VERSION 5.8 ;
BUSBITCHARS "[]" ;
DIVIDERCHAR "/" ;
UNITS
    DATABASE MICRONS 1000 ;
END UNITS

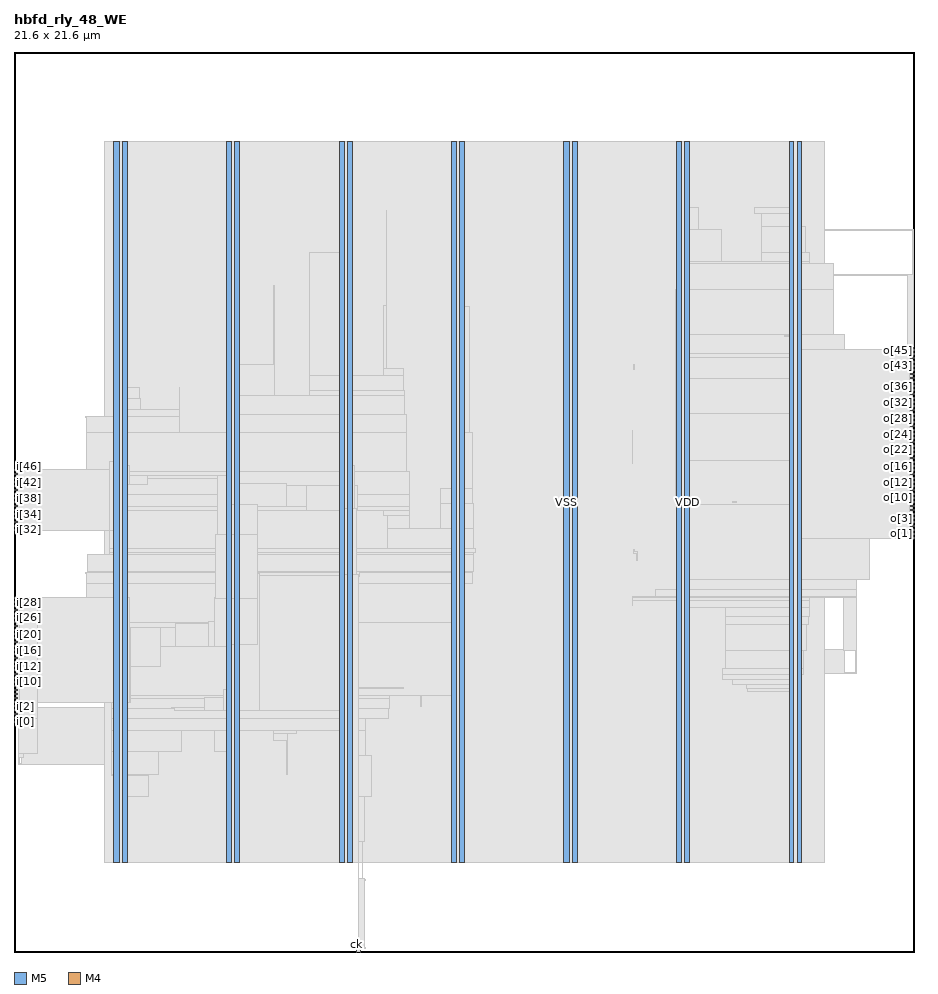
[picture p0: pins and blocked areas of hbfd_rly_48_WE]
MACRO hbfd_rly_48_WE
  FOREIGN hbfd_rly_48_WE 0 0 ;
  CLASS BLOCK ;
  SIZE 21.6 BY 21.6 ;
  PIN ck
    DIRECTION INPUT ;
    USE SIGNAL ;
    PORT
      LAYER M5 ;
        RECT  8.208 0 8.232 0.084 ;
    END
  END ck
  PIN i[0]
    DIRECTION INPUT ;
    USE SIGNAL ;
    PORT
      LAYER M4 ;
        RECT  0 5.52 0.084 5.544 ;
    END
  END i[0]
  PIN i[10]
    DIRECTION INPUT ;
    USE SIGNAL ;
    PORT
      LAYER M4 ;
        RECT  0 6.48 0.084 6.504 ;
    END
  END i[10]
  PIN i[11]
    DIRECTION INPUT ;
    USE SIGNAL ;
    PORT
      LAYER M4 ;
        RECT  0 6.576 0.084 6.6 ;
    END
  END i[11]
  PIN i[12]
    DIRECTION INPUT ;
    USE SIGNAL ;
    PORT
      LAYER M4 ;
        RECT  0 6.672 0.084 6.696 ;
    END
  END i[12]
  PIN i[13]
    DIRECTION INPUT ;
    USE SIGNAL ;
    PORT
      LAYER M4 ;
        RECT  0 6.768 0.084 6.792 ;
    END
  END i[13]
  PIN i[14]
    DIRECTION INPUT ;
    USE SIGNAL ;
    PORT
      LAYER M4 ;
        RECT  0 6.864 0.084 6.888 ;
    END
  END i[14]
  PIN i[15]
    DIRECTION INPUT ;
    USE SIGNAL ;
    PORT
      LAYER M4 ;
        RECT  0 6.96 0.084 6.984 ;
    END
  END i[15]
  PIN i[16]
    DIRECTION INPUT ;
    USE SIGNAL ;
    PORT
      LAYER M4 ;
        RECT  0 7.056 0.084 7.08 ;
    END
  END i[16]
  PIN i[17]
    DIRECTION INPUT ;
    USE SIGNAL ;
    PORT
      LAYER M4 ;
        RECT  0 7.152 0.084 7.176 ;
    END
  END i[17]
  PIN i[18]
    DIRECTION INPUT ;
    USE SIGNAL ;
    PORT
      LAYER M4 ;
        RECT  0 7.248 0.084 7.272 ;
    END
  END i[18]
  PIN i[19]
    DIRECTION INPUT ;
    USE SIGNAL ;
    PORT
      LAYER M4 ;
        RECT  0 7.344 0.084 7.368 ;
    END
  END i[19]
  PIN i[1]
    DIRECTION INPUT ;
    USE SIGNAL ;
    PORT
      LAYER M4 ;
        RECT  0 5.616 0.084 5.64 ;
    END
  END i[1]
  PIN i[20]
    DIRECTION INPUT ;
    USE SIGNAL ;
    PORT
      LAYER M4 ;
        RECT  0 7.44 0.084 7.464 ;
    END
  END i[20]
  PIN i[21]
    DIRECTION INPUT ;
    USE SIGNAL ;
    PORT
      LAYER M4 ;
        RECT  0 7.536 0.084 7.56 ;
    END
  END i[21]
  PIN i[22]
    DIRECTION INPUT ;
    USE SIGNAL ;
    PORT
      LAYER M4 ;
        RECT  0 7.632 0.084 7.656 ;
    END
  END i[22]
  PIN i[23]
    DIRECTION INPUT ;
    USE SIGNAL ;
    PORT
      LAYER M4 ;
        RECT  0 7.728 0.084 7.752 ;
    END
  END i[23]
  PIN i[24]
    DIRECTION INPUT ;
    USE SIGNAL ;
    PORT
      LAYER M4 ;
        RECT  0 7.824 0.084 7.848 ;
    END
  END i[24]
  PIN i[25]
    DIRECTION INPUT ;
    USE SIGNAL ;
    PORT
      LAYER M4 ;
        RECT  0 7.92 0.084 7.944 ;
    END
  END i[25]
  PIN i[26]
    DIRECTION INPUT ;
    USE SIGNAL ;
    PORT
      LAYER M4 ;
        RECT  0 8.016 0.084 8.04 ;
    END
  END i[26]
  PIN i[27]
    DIRECTION INPUT ;
    USE SIGNAL ;
    PORT
      LAYER M4 ;
        RECT  0 8.112 0.084 8.136 ;
    END
  END i[27]
  PIN i[28]
    DIRECTION INPUT ;
    USE SIGNAL ;
    PORT
      LAYER M4 ;
        RECT  0 8.208 0.084 8.232 ;
    END
  END i[28]
  PIN i[29]
    DIRECTION INPUT ;
    USE SIGNAL ;
    PORT
      LAYER M4 ;
        RECT  0 8.304 0.084 8.328 ;
    END
  END i[29]
  PIN i[2]
    DIRECTION INPUT ;
    USE SIGNAL ;
    PORT
      LAYER M4 ;
        RECT  0 5.712 0.084 5.736 ;
    END
  END i[2]
  PIN i[30]
    DIRECTION INPUT ;
    USE SIGNAL ;
    PORT
      LAYER M4 ;
        RECT  0 8.4 0.084 8.424 ;
    END
  END i[30]
  PIN i[31]
    DIRECTION INPUT ;
    USE SIGNAL ;
    PORT
      LAYER M4 ;
        RECT  0 8.496 0.084 8.52 ;
    END
  END i[31]
  PIN i[32]
    DIRECTION INPUT ;
    USE SIGNAL ;
    PORT
      LAYER M4 ;
        RECT  0 10.128 0.084 10.152 ;
    END
  END i[32]
  PIN i[33]
    DIRECTION INPUT ;
    USE SIGNAL ;
    PORT
      LAYER M4 ;
        RECT  0 10.224 0.084 10.248 ;
    END
  END i[33]
  PIN i[34]
    DIRECTION INPUT ;
    USE SIGNAL ;
    PORT
      LAYER M4 ;
        RECT  0 10.32 0.084 10.344 ;
    END
  END i[34]
  PIN i[35]
    DIRECTION INPUT ;
    USE SIGNAL ;
    PORT
      LAYER M4 ;
        RECT  0 10.416 0.084 10.44 ;
    END
  END i[35]
  PIN i[36]
    DIRECTION INPUT ;
    USE SIGNAL ;
    PORT
      LAYER M4 ;
        RECT  0 10.512 0.084 10.536 ;
    END
  END i[36]
  PIN i[37]
    DIRECTION INPUT ;
    USE SIGNAL ;
    PORT
      LAYER M4 ;
        RECT  0 10.608 0.084 10.632 ;
    END
  END i[37]
  PIN i[38]
    DIRECTION INPUT ;
    USE SIGNAL ;
    PORT
      LAYER M4 ;
        RECT  0 10.704 0.084 10.728 ;
    END
  END i[38]
  PIN i[39]
    DIRECTION INPUT ;
    USE SIGNAL ;
    PORT
      LAYER M4 ;
        RECT  0 10.8 0.084 10.824 ;
    END
  END i[39]
  PIN i[3]
    DIRECTION INPUT ;
    USE SIGNAL ;
    PORT
      LAYER M4 ;
        RECT  0 5.808 0.084 5.832 ;
    END
  END i[3]
  PIN i[40]
    DIRECTION INPUT ;
    USE SIGNAL ;
    PORT
      LAYER M4 ;
        RECT  0 10.896 0.084 10.92 ;
    END
  END i[40]
  PIN i[41]
    DIRECTION INPUT ;
    USE SIGNAL ;
    PORT
      LAYER M4 ;
        RECT  0 10.992 0.084 11.016 ;
    END
  END i[41]
  PIN i[42]
    DIRECTION INPUT ;
    USE SIGNAL ;
    PORT
      LAYER M4 ;
        RECT  0 11.088 0.084 11.112 ;
    END
  END i[42]
  PIN i[43]
    DIRECTION INPUT ;
    USE SIGNAL ;
    PORT
      LAYER M4 ;
        RECT  0 11.184 0.084 11.208 ;
    END
  END i[43]
  PIN i[44]
    DIRECTION INPUT ;
    USE SIGNAL ;
    PORT
      LAYER M4 ;
        RECT  0 11.28 0.084 11.304 ;
    END
  END i[44]
  PIN i[45]
    DIRECTION INPUT ;
    USE SIGNAL ;
    PORT
      LAYER M4 ;
        RECT  0 11.376 0.084 11.4 ;
    END
  END i[45]
  PIN i[46]
    DIRECTION INPUT ;
    USE SIGNAL ;
    PORT
      LAYER M4 ;
        RECT  0 11.472 0.084 11.496 ;
    END
  END i[46]
  PIN i[47]
    DIRECTION INPUT ;
    USE SIGNAL ;
    PORT
      LAYER M4 ;
        RECT  0 11.568 0.084 11.592 ;
    END
  END i[47]
  PIN i[4]
    DIRECTION INPUT ;
    USE SIGNAL ;
    PORT
      LAYER M4 ;
        RECT  0 5.904 0.084 5.928 ;
    END
  END i[4]
  PIN i[5]
    DIRECTION INPUT ;
    USE SIGNAL ;
    PORT
      LAYER M4 ;
        RECT  0 6 0.084 6.024 ;
    END
  END i[5]
  PIN i[6]
    DIRECTION INPUT ;
    USE SIGNAL ;
    PORT
      LAYER M4 ;
        RECT  0 6.096 0.084 6.12 ;
    END
  END i[6]
  PIN i[7]
    DIRECTION INPUT ;
    USE SIGNAL ;
    PORT
      LAYER M4 ;
        RECT  0 6.192 0.084 6.216 ;
    END
  END i[7]
  PIN i[8]
    DIRECTION INPUT ;
    USE SIGNAL ;
    PORT
      LAYER M4 ;
        RECT  0 6.288 0.084 6.312 ;
    END
  END i[8]
  PIN i[9]
    DIRECTION INPUT ;
    USE SIGNAL ;
    PORT
      LAYER M4 ;
        RECT  0 6.384 0.084 6.408 ;
    END
  END i[9]
  PIN o[0]
    DIRECTION OUTPUT ;
    USE SIGNAL ;
    PORT
      LAYER M4 ;
        RECT  21.516 9.936 21.6 9.96 ;
    END
  END o[0]
  PIN o[10]
    DIRECTION OUTPUT ;
    USE SIGNAL ;
    PORT
      LAYER M4 ;
        RECT  21.516 10.896 21.6 10.92 ;
    END
  END o[10]
  PIN o[11]
    DIRECTION OUTPUT ;
    USE SIGNAL ;
    PORT
      LAYER M4 ;
        RECT  21.516 10.992 21.6 11.016 ;
    END
  END o[11]
  PIN o[12]
    DIRECTION OUTPUT ;
    USE SIGNAL ;
    PORT
      LAYER M4 ;
        RECT  21.516 11.088 21.6 11.112 ;
    END
  END o[12]
  PIN o[13]
    DIRECTION OUTPUT ;
    USE SIGNAL ;
    PORT
      LAYER M4 ;
        RECT  21.516 11.184 21.6 11.208 ;
    END
  END o[13]
  PIN o[14]
    DIRECTION OUTPUT ;
    USE SIGNAL ;
    PORT
      LAYER M4 ;
        RECT  21.516 11.28 21.6 11.304 ;
    END
  END o[14]
  PIN o[15]
    DIRECTION OUTPUT ;
    USE SIGNAL ;
    PORT
      LAYER M4 ;
        RECT  21.516 11.376 21.6 11.4 ;
    END
  END o[15]
  PIN o[16]
    DIRECTION OUTPUT ;
    USE SIGNAL ;
    PORT
      LAYER M4 ;
        RECT  21.516 11.472 21.6 11.496 ;
    END
  END o[16]
  PIN o[17]
    DIRECTION OUTPUT ;
    USE SIGNAL ;
    PORT
      LAYER M4 ;
        RECT  21.516 11.568 21.6 11.592 ;
    END
  END o[17]
  PIN o[18]
    DIRECTION OUTPUT ;
    USE SIGNAL ;
    PORT
      LAYER M4 ;
        RECT  21.516 11.664 21.6 11.688 ;
    END
  END o[18]
  PIN o[19]
    DIRECTION OUTPUT ;
    USE SIGNAL ;
    PORT
      LAYER M4 ;
        RECT  21.516 11.76 21.6 11.784 ;
    END
  END o[19]
  PIN o[1]
    DIRECTION OUTPUT ;
    USE SIGNAL ;
    PORT
      LAYER M4 ;
        RECT  21.516 10.032 21.6 10.056 ;
    END
  END o[1]
  PIN o[20]
    DIRECTION OUTPUT ;
    USE SIGNAL ;
    PORT
      LAYER M4 ;
        RECT  21.516 11.856 21.6 11.88 ;
    END
  END o[20]
  PIN o[21]
    DIRECTION OUTPUT ;
    USE SIGNAL ;
    PORT
      LAYER M4 ;
        RECT  21.516 11.952 21.6 11.976 ;
    END
  END o[21]
  PIN o[22]
    DIRECTION OUTPUT ;
    USE SIGNAL ;
    PORT
      LAYER M4 ;
        RECT  21.516 12.048 21.6 12.072 ;
    END
  END o[22]
  PIN o[23]
    DIRECTION OUTPUT ;
    USE SIGNAL ;
    PORT
      LAYER M4 ;
        RECT  21.516 12.144 21.6 12.168 ;
    END
  END o[23]
  PIN o[24]
    DIRECTION OUTPUT ;
    USE SIGNAL ;
    PORT
      LAYER M4 ;
        RECT  21.516 12.24 21.6 12.264 ;
    END
  END o[24]
  PIN o[25]
    DIRECTION OUTPUT ;
    USE SIGNAL ;
    PORT
      LAYER M4 ;
        RECT  21.516 12.336 21.6 12.36 ;
    END
  END o[25]
  PIN o[26]
    DIRECTION OUTPUT ;
    USE SIGNAL ;
    PORT
      LAYER M4 ;
        RECT  21.516 12.432 21.6 12.456 ;
    END
  END o[26]
  PIN o[27]
    DIRECTION OUTPUT ;
    USE SIGNAL ;
    PORT
      LAYER M4 ;
        RECT  21.516 12.528 21.6 12.552 ;
    END
  END o[27]
  PIN o[28]
    DIRECTION OUTPUT ;
    USE SIGNAL ;
    PORT
      LAYER M4 ;
        RECT  21.516 12.624 21.6 12.648 ;
    END
  END o[28]
  PIN o[29]
    DIRECTION OUTPUT ;
    USE SIGNAL ;
    PORT
      LAYER M4 ;
        RECT  21.516 12.72 21.6 12.744 ;
    END
  END o[29]
  PIN o[2]
    DIRECTION OUTPUT ;
    USE SIGNAL ;
    PORT
      LAYER M4 ;
        RECT  21.516 10.128 21.6 10.152 ;
    END
  END o[2]
  PIN o[30]
    DIRECTION OUTPUT ;
    USE SIGNAL ;
    PORT
      LAYER M4 ;
        RECT  21.516 12.816 21.6 12.84 ;
    END
  END o[30]
  PIN o[31]
    DIRECTION OUTPUT ;
    USE SIGNAL ;
    PORT
      LAYER M4 ;
        RECT  21.516 12.912 21.6 12.936 ;
    END
  END o[31]
  PIN o[32]
    DIRECTION OUTPUT ;
    USE SIGNAL ;
    PORT
      LAYER M4 ;
        RECT  21.516 13.008 21.6 13.032 ;
    END
  END o[32]
  PIN o[33]
    DIRECTION OUTPUT ;
    USE SIGNAL ;
    PORT
      LAYER M4 ;
        RECT  21.516 13.104 21.6 13.128 ;
    END
  END o[33]
  PIN o[34]
    DIRECTION OUTPUT ;
    USE SIGNAL ;
    PORT
      LAYER M4 ;
        RECT  21.516 13.2 21.6 13.224 ;
    END
  END o[34]
  PIN o[35]
    DIRECTION OUTPUT ;
    USE SIGNAL ;
    PORT
      LAYER M4 ;
        RECT  21.516 13.296 21.6 13.32 ;
    END
  END o[35]
  PIN o[36]
    DIRECTION OUTPUT ;
    USE SIGNAL ;
    PORT
      LAYER M4 ;
        RECT  21.516 13.392 21.6 13.416 ;
    END
  END o[36]
  PIN o[37]
    DIRECTION OUTPUT ;
    USE SIGNAL ;
    PORT
      LAYER M4 ;
        RECT  21.516 13.488 21.6 13.512 ;
    END
  END o[37]
  PIN o[38]
    DIRECTION OUTPUT ;
    USE SIGNAL ;
    PORT
      LAYER M4 ;
        RECT  21.516 13.584 21.6 13.608 ;
    END
  END o[38]
  PIN o[39]
    DIRECTION OUTPUT ;
    USE SIGNAL ;
    PORT
      LAYER M4 ;
        RECT  21.516 13.68 21.6 13.704 ;
    END
  END o[39]
  PIN o[3]
    DIRECTION OUTPUT ;
    USE SIGNAL ;
    PORT
      LAYER M4 ;
        RECT  21.516 10.224 21.6 10.248 ;
    END
  END o[3]
  PIN o[40]
    DIRECTION OUTPUT ;
    USE SIGNAL ;
    PORT
      LAYER M4 ;
        RECT  21.516 13.776 21.6 13.8 ;
    END
  END o[40]
  PIN o[41]
    DIRECTION OUTPUT ;
    USE SIGNAL ;
    PORT
      LAYER M4 ;
        RECT  21.516 13.872 21.6 13.896 ;
    END
  END o[41]
  PIN o[42]
    DIRECTION OUTPUT ;
    USE SIGNAL ;
    PORT
      LAYER M4 ;
        RECT  21.516 13.968 21.6 13.992 ;
    END
  END o[42]
  PIN o[43]
    DIRECTION OUTPUT ;
    USE SIGNAL ;
    PORT
      LAYER M4 ;
        RECT  21.516 14.064 21.6 14.088 ;
    END
  END o[43]
  PIN o[44]
    DIRECTION OUTPUT ;
    USE SIGNAL ;
    PORT
      LAYER M4 ;
        RECT  21.516 14.16 21.6 14.184 ;
    END
  END o[44]
  PIN o[45]
    DIRECTION OUTPUT ;
    USE SIGNAL ;
    PORT
      LAYER M4 ;
        RECT  21.516 14.256 21.6 14.28 ;
    END
  END o[45]
  PIN o[46]
    DIRECTION OUTPUT ;
    USE SIGNAL ;
    PORT
      LAYER M4 ;
        RECT  21.516 14.352 21.6 14.376 ;
    END
  END o[46]
  PIN o[47]
    DIRECTION OUTPUT ;
    USE SIGNAL ;
    PORT
      LAYER M4 ;
        RECT  21.516 14.448 21.6 14.472 ;
    END
  END o[47]
  PIN o[4]
    DIRECTION OUTPUT ;
    USE SIGNAL ;
    PORT
      LAYER M4 ;
        RECT  21.516 10.32 21.6 10.344 ;
    END
  END o[4]
  PIN o[5]
    DIRECTION OUTPUT ;
    USE SIGNAL ;
    PORT
      LAYER M4 ;
        RECT  21.516 10.416 21.6 10.44 ;
    END
  END o[5]
  PIN o[6]
    DIRECTION OUTPUT ;
    USE SIGNAL ;
    PORT
      LAYER M4 ;
        RECT  21.516 10.512 21.6 10.536 ;
    END
  END o[6]
  PIN o[7]
    DIRECTION OUTPUT ;
    USE SIGNAL ;
    PORT
      LAYER M4 ;
        RECT  21.516 10.608 21.6 10.632 ;
    END
  END o[7]
  PIN o[8]
    DIRECTION OUTPUT ;
    USE SIGNAL ;
    PORT
      LAYER M4 ;
        RECT  21.516 10.704 21.6 10.728 ;
    END
  END o[8]
  PIN o[9]
    DIRECTION OUTPUT ;
    USE SIGNAL ;
    PORT
      LAYER M4 ;
        RECT  21.516 10.8 21.6 10.824 ;
    END
  END o[9]
  PIN rs
    DIRECTION INPUT ;
    USE SIGNAL ;
    PORT
      LAYER M5 ;
        RECT  8.304 0 8.328 0.084 ;
    END
  END rs
  PIN VDD
    DIRECTION INOUT ;
    USE POWER ;
    PORT
      LAYER M5 ;
        RECT  18.792 2.151 18.912 19.449 ;
        RECT  16.092 2.151 16.212 19.449 ;
        RECT  13.392 2.151 13.512 19.449 ;
        RECT  10.692 2.151 10.812 19.449 ;
        RECT  7.992 2.151 8.112 19.449 ;
        RECT  5.292 2.151 5.412 19.449 ;
        RECT  2.592 2.151 2.712 19.449 ;
    END
  END VDD
  PIN VSS
    DIRECTION INOUT ;
    USE GROUND ;
    PORT
      LAYER M5 ;
        RECT  18.6 2.137 18.72 19.463 ;
        RECT  15.9 2.137 16.02 19.463 ;
        RECT  13.2 2.137 13.32 19.463 ;
        RECT  10.5 2.137 10.62 19.463 ;
        RECT  7.8 2.137 7.92 19.463 ;
        RECT  5.1 2.137 5.22 19.463 ;
        RECT  2.4 2.137 2.52 19.463 ;
    END
  END VSS
  # OT_OBS_CLOSED layer=M5 d_um=1.536 added=0
  OBS
    LAYER RVTN ;
     RECT  2.16 2.16 19.44 2.295 ;
     RECT  2.16 2.565 19.44 2.835 ;
     RECT  2.16 3.105 19.44 3.375 ;
     RECT  2.16 3.645 19.44 3.915 ;
     RECT  2.16 4.185 19.44 4.455 ;
     RECT  2.16 4.725 19.44 4.995 ;
     RECT  2.16 5.265 19.44 5.535 ;
     RECT  2.16 5.805 19.44 6.075 ;
     RECT  2.16 6.345 19.44 6.615 ;
     RECT  2.16 6.885 19.44 7.155 ;
     RECT  2.16 7.425 19.44 7.695 ;
     RECT  2.16 7.965 19.44 8.235 ;
     RECT  2.16 8.505 19.44 8.775 ;
     RECT  2.16 9.045 19.44 9.315 ;
     RECT  2.16 9.585 19.44 9.855 ;
     RECT  2.16 10.125 19.44 10.395 ;
     RECT  2.16 10.665 19.44 10.935 ;
     RECT  2.16 11.205 19.44 11.475 ;
     RECT  2.16 11.745 19.44 12.015 ;
     RECT  2.16 12.285 19.44 12.555 ;
     RECT  2.16 12.825 19.44 13.095 ;
     RECT  2.16 13.365 19.44 13.635 ;
     RECT  2.16 13.905 19.44 14.175 ;
     RECT  2.16 14.445 19.44 14.715 ;
     RECT  2.16 14.985 19.44 15.255 ;
     RECT  2.16 15.525 19.44 15.795 ;
     RECT  2.16 16.065 19.44 16.335 ;
     RECT  2.16 16.605 19.44 16.875 ;
     RECT  2.16 17.145 19.44 17.415 ;
     RECT  2.16 17.685 19.44 17.955 ;
     RECT  2.16 18.225 19.44 18.495 ;
     RECT  2.16 18.765 19.44 19.035 ;
     RECT  2.16 19.305 19.44 19.44 ;
    LAYER RVTP ;
     RECT  2.16 2.295 19.44 2.565 ;
     RECT  2.16 2.835 19.44 3.105 ;
     RECT  2.16 3.375 19.44 3.645 ;
     RECT  2.16 3.915 19.44 4.185 ;
     RECT  2.16 4.455 19.44 4.725 ;
     RECT  2.16 4.995 19.44 5.265 ;
     RECT  2.16 5.535 19.44 5.805 ;
     RECT  2.16 6.075 19.44 6.345 ;
     RECT  2.16 6.615 19.44 6.885 ;
     RECT  2.16 7.155 19.44 7.425 ;
     RECT  2.16 7.695 19.44 7.965 ;
     RECT  2.16 8.235 19.44 8.505 ;
     RECT  2.16 8.775 19.44 9.045 ;
     RECT  2.16 9.315 19.44 9.585 ;
     RECT  2.16 9.855 19.44 10.125 ;
     RECT  2.16 10.395 19.44 10.665 ;
     RECT  2.16 10.935 19.44 11.205 ;
     RECT  2.16 11.475 19.44 11.745 ;
     RECT  2.16 12.015 19.44 12.285 ;
     RECT  2.16 12.555 19.44 12.825 ;
     RECT  2.16 13.095 19.44 13.365 ;
     RECT  2.16 13.635 19.44 13.905 ;
     RECT  2.16 14.175 19.44 14.445 ;
     RECT  2.16 14.715 19.44 14.985 ;
     RECT  2.16 15.255 19.44 15.525 ;
     RECT  2.16 15.795 19.44 16.065 ;
     RECT  2.16 16.335 19.44 16.605 ;
     RECT  2.16 16.875 19.44 17.145 ;
     RECT  2.16 17.415 19.44 17.685 ;
     RECT  2.16 17.955 19.44 18.225 ;
     RECT  2.16 18.495 19.44 18.765 ;
     RECT  2.16 19.035 19.44 19.305 ;
    LAYER M1 ;
     RECT  2.16 2.151 19.44 19.449 ;
    LAYER M2 ;
     RECT  0.103 5.85 0.139 5.868 ;
     RECT  0.103 6.822 0.139 7.416 ;
     RECT  0.103 4.5 0.175 4.518 ;
     RECT  0.139 5.58 0.175 5.868 ;
     RECT  1.723 9.09 1.759 9.108 ;
     RECT  1.723 12.834 1.975 12.852 ;
     RECT  1.975 12.33 2.011 12.852 ;
     RECT  0.175 4.5 2.16 5.868 ;
     RECT  0.139 6.786 2.16 7.416 ;
     RECT  1.759 9.09 2.16 9.54 ;
     RECT  2.011 12.294 2.16 12.852 ;
     RECT  2.16 2.151 19.44 19.449 ;
     RECT  19.44 10.134 19.463 15.084 ;
     RECT  19.44 15.876 19.499 16.524 ;
     RECT  19.499 16.236 19.679 16.524 ;
     RECT  19.44 6.696 19.931 7.254 ;
     RECT  19.463 10.134 19.931 14.814 ;
     RECT  19.931 6.696 20.219 6.714 ;
     RECT  19.931 10.134 20.471 14.364 ;
     RECT  20.471 10.134 20.507 14.274 ;
     RECT  19.44 8.946 20.543 8.964 ;
     RECT  20.507 11.016 20.543 11.16 ;
     RECT  19.679 16.236 21.479 16.254 ;
     RECT  20.507 10.134 21.515 10.152 ;
     RECT  20.543 11.142 21.515 11.16 ;
     RECT  20.507 11.952 21.515 12.546 ;
     RECT  20.507 13.446 21.515 13.464 ;
     RECT  19.44 17.316 21.587 17.334 ;
    LAYER M3 ;
     RECT  8.352 1.723 8.37 2.143 ;
     RECT  2.415 2.143 2.505 2.413 ;
     RECT  5.115 2.143 5.205 2.413 ;
     RECT  10.515 2.143 10.605 2.413 ;
     RECT  13.215 2.143 13.305 2.413 ;
     RECT  15.915 2.143 16.005 2.413 ;
     RECT  18.615 2.143 18.705 2.413 ;
     RECT  7.815 2.143 8.37 2.641 ;
     RECT  2.415 2.413 2.697 3.721 ;
     RECT  7.815 2.641 8.406 3.721 ;
     RECT  2.415 3.721 3.222 4.225 ;
     RECT  2.34 4.225 3.222 4.261 ;
     RECT  0.108 4.495 0.126 4.657 ;
     RECT  7.815 3.721 8.586 4.721 ;
     RECT  0.108 4.657 0.234 4.765 ;
     RECT  2.34 4.261 3.474 4.801 ;
     RECT  5.115 2.413 5.397 4.801 ;
     RECT  6.552 4.261 6.57 5.071 ;
     RECT  6.228 5.071 6.57 5.233 ;
     RECT  2.34 4.801 4.014 5.305 ;
     RECT  4.824 4.801 5.397 5.305 ;
     RECT  6.228 5.233 6.786 5.305 ;
     RECT  7.815 4.721 8.442 5.305 ;
     RECT  2.34 5.305 8.442 5.611 ;
     RECT  0.108 4.765 0.558 5.645 ;
     RECT  0.108 5.645 0.522 5.741 ;
     RECT  2.34 5.611 8.982 5.845 ;
     RECT  2.34 5.845 9.018 6.091 ;
     RECT  2.304 6.091 9.018 6.151 ;
     RECT  9.756 5.881 9.774 6.151 ;
     RECT  10.515 2.413 10.797 6.151 ;
     RECT  18.615 2.413 18.897 6.241 ;
     RECT  17.604 6.241 18.897 6.313 ;
     RECT  0.108 5.741 0.306 6.317 ;
     RECT  17.568 6.313 18.897 6.421 ;
     RECT  17.244 6.421 18.897 6.547 ;
     RECT  16.992 6.547 18.897 6.655 ;
     RECT  16.992 6.655 18.954 6.809 ;
     RECT  17.064 6.809 18.954 7.231 ;
     RECT  20.196 6.691 20.214 7.231 ;
     RECT  0.108 6.317 0.162 7.531 ;
     RECT  0.108 7.531 0.342 7.661 ;
     RECT  17.064 7.231 19.026 7.861 ;
     RECT  2.304 6.151 10.797 7.915 ;
     RECT  17.064 7.861 19.062 8.041 ;
     RECT  15.915 2.413 16.197 8.275 ;
     RECT  17.064 8.041 19.098 8.275 ;
     RECT  14.832 8.311 14.85 8.437 ;
     RECT  15.915 8.275 19.098 8.437 ;
     RECT  14.832 8.437 19.098 8.509 ;
     RECT  19.908 7.231 20.214 8.509 ;
     RECT  14.832 8.509 20.214 8.537 ;
     RECT  15.408 8.537 20.214 8.699 ;
     RECT  1.728 7.915 10.797 8.851 ;
     RECT  15.915 8.699 20.214 8.941 ;
     RECT  1.728 8.851 10.998 9.113 ;
     RECT  1.764 9.113 10.998 9.121 ;
     RECT  1.764 9.121 11.034 9.545 ;
     RECT  14.94 9.391 14.958 9.553 ;
     RECT  2.304 9.545 11.034 9.589 ;
     RECT  14.868 9.553 14.958 9.617 ;
     RECT  14.868 9.617 14.886 9.653 ;
     RECT  2.304 9.589 11.07 9.689 ;
     RECT  8.964 9.689 11.034 10.157 ;
     RECT  8.964 10.157 9.486 10.471 ;
     RECT  2.304 9.689 8.097 10.603 ;
     RECT  8.856 10.471 9.486 10.603 ;
     RECT  21.492 10.129 21.51 10.651 ;
     RECT  2.304 10.603 9.486 10.699 ;
     RECT  15.915 8.941 20.538 10.741 ;
     RECT  10.224 10.157 11.034 10.769 ;
     RECT  21.42 10.651 21.51 10.829 ;
     RECT  1.98 10.699 9.486 10.987 ;
     RECT  10.224 10.769 10.998 11.129 ;
     RECT  0.144 11.227 0.162 11.405 ;
     RECT  1.728 10.987 9.486 11.543 ;
     RECT  15.876 10.741 20.538 11.789 ;
     RECT  1.728 11.543 9.414 12.479 ;
     RECT  10.515 11.129 10.998 12.479 ;
     RECT  14.832 11.713 14.85 12.515 ;
     RECT  1.728 12.479 3.978 12.857 ;
     RECT  5.115 12.479 9.414 12.893 ;
     RECT  15.876 11.789 20.502 12.929 ;
     RECT  2.415 12.857 3.978 13.019 ;
     RECT  2.415 13.019 3.042 13.289 ;
     RECT  5.115 12.893 9.378 13.361 ;
     RECT  7.092 13.361 9.378 13.469 ;
     RECT  21.492 10.829 21.51 13.469 ;
     RECT  2.415 13.289 3.006 13.559 ;
     RECT  3.96 13.019 3.978 13.559 ;
     RECT  19.872 12.929 20.502 13.675 ;
     RECT  15.876 12.929 19.098 13.771 ;
     RECT  19.836 13.675 20.502 13.771 ;
     RECT  7.092 13.469 9.342 13.829 ;
     RECT  8.856 13.829 9.342 14.009 ;
     RECT  5.115 13.361 6.246 14.099 ;
     RECT  14.868 13.981 14.886 14.099 ;
     RECT  21.456 13.579 21.474 14.251 ;
     RECT  15.876 13.771 20.502 14.279 ;
     RECT  15.876 14.279 20.466 14.369 ;
     RECT  21.456 14.251 21.51 14.539 ;
     RECT  15.876 14.369 19.926 14.819 ;
     RECT  10.515 12.479 10.926 15.485 ;
     RECT  8.856 14.009 8.946 15.521 ;
     RECT  15.876 14.819 19.674 15.899 ;
     RECT  6.228 14.099 6.246 15.989 ;
     RECT  21.456 14.539 21.582 16.259 ;
     RECT  15.915 15.899 19.674 16.529 ;
     RECT  15.915 16.529 19.098 16.565 ;
     RECT  7.092 13.829 8.097 16.799 ;
     RECT  17.928 16.565 19.098 16.799 ;
     RECT  15.915 16.565 16.974 17.339 ;
     RECT  21.564 16.259 21.582 17.339 ;
     RECT  17.928 16.799 18.99 17.411 ;
     RECT  17.928 17.411 18.897 17.725 ;
     RECT  8.928 15.521 8.946 17.789 ;
     RECT  15.915 17.339 16.434 17.879 ;
     RECT  17.784 17.725 18.897 17.879 ;
     RECT  2.415 13.559 2.697 19.187 ;
     RECT  5.115 14.099 5.397 19.187 ;
     RECT  7.815 16.799 8.097 19.187 ;
     RECT  10.515 15.485 10.797 19.187 ;
     RECT  13.215 2.413 13.497 19.187 ;
     RECT  15.915 17.879 16.197 19.187 ;
     RECT  18.615 17.879 18.897 19.187 ;
     RECT  2.415 19.187 2.505 19.457 ;
     RECT  5.115 19.187 5.205 19.457 ;
     RECT  7.815 19.187 7.905 19.457 ;
     RECT  10.515 19.187 10.605 19.457 ;
     RECT  13.215 19.187 13.305 19.457 ;
     RECT  15.915 19.187 16.005 19.457 ;
     RECT  18.615 19.187 18.705 19.457 ;
    LAYER M4 ;
     RECT  0.06 5.52 0.137 8.52 ;
     RECT  0.137 5.616 0.569 8.52 ;
     RECT  0.06 10.128 2.293 11.592 ;
     RECT  0.569 6 2.408 8.52 ;
     RECT  2.293 10.128 2.408 11.784 ;
     RECT  2.408 2.148 2.512 19.452 ;
     RECT  2.512 2.418 2.704 19.182 ;
     RECT  2.704 6 2.765 8.52 ;
     RECT  2.704 11.232 2.765 11.688 ;
     RECT  2.765 6 2.801 7.8 ;
     RECT  2.765 11.232 3.197 11.448 ;
     RECT  2.801 6.864 3.521 7.8 ;
     RECT  3.769 5.856 3.841 5.88 ;
     RECT  3.521 7.344 3.877 7.8 ;
     RECT  3.841 5.808 4.561 5.88 ;
     RECT  3.877 7.344 4.669 7.896 ;
     RECT  4.669 7.344 4.813 7.944 ;
     RECT  4.837 9.984 4.885 10.008 ;
     RECT  3.197 11.376 4.885 11.448 ;
     RECT  4.561 5.808 5.029 6.12 ;
     RECT  5.029 5.808 5.108 6.312 ;
     RECT  4.813 7.344 5.108 8.52 ;
     RECT  4.885 9.984 5.108 11.448 ;
     RECT  5.108 2.148 5.212 19.452 ;
     RECT  5.212 2.418 5.404 19.182 ;
     RECT  5.404 5.808 5.884 9.096 ;
     RECT  5.404 10.704 6.545 11.256 ;
     RECT  6.545 10.704 7.009 11.208 ;
     RECT  5.884 5.808 7.808 9.048 ;
     RECT  7.009 10.608 7.808 11.208 ;
     RECT  7.808 2.148 7.912 19.452 ;
     RECT  7.912 2.148 8.104 19.182 ;
     RECT  8.104 7.344 8.165 7.368 ;
     RECT  8.104 10.608 8.165 11.688 ;
     RECT  8.104 6.096 8.201 6.36 ;
     RECT  8.165 10.608 8.237 11.208 ;
     RECT  8.237 10.608 8.243 10.632 ;
     RECT  8.104 9.024 8.281 9.144 ;
     RECT  8.101 0.096 8.291 0.216 ;
     RECT  8.281 9.024 8.291 9.048 ;
     RECT  8.291 0.096 8.435 0.12 ;
     RECT  8.341 1.728 8.435 1.752 ;
     RECT  8.201 6.336 9.353 6.36 ;
     RECT  10.508 2.148 10.612 19.452 ;
     RECT  10.612 2.418 10.804 19.182 ;
     RECT  13.208 2.148 13.312 19.452 ;
     RECT  13.312 2.418 13.504 19.182 ;
     RECT  15.908 2.148 16.012 19.452 ;
     RECT  16.012 2.418 16.204 19.182 ;
     RECT  17.233 10.8 17.345 10.824 ;
     RECT  18.493 14.784 18.608 14.808 ;
     RECT  18.608 2.148 18.712 19.452 ;
     RECT  18.712 2.418 18.904 19.182 ;
     RECT  18.904 9.936 21.481 14.472 ;
     RECT  21.481 9.936 21.564 14.568 ;
     RECT  21.564 14.544 21.593 14.568 ;
    LAYER M5 ;
     RECT  8.208 0.016 8.328 0.085 ;
     RECT  8.112 0.085 8.424 0.227 ;
     RECT  8.256 0.227 8.424 1.763 ;
     RECT  8.256 1.763 8.28 2.137 ;
     RECT  2.4 2.137 2.52 2.151 ;
     RECT  5.1 2.137 5.22 2.151 ;
     RECT  10.5 2.137 10.62 2.151 ;
     RECT  13.2 2.137 13.32 2.151 ;
     RECT  15.9 2.137 16.02 2.151 ;
     RECT  18.6 2.137 18.72 2.151 ;
     RECT  5.1 2.151 5.412 7.381 ;
     RECT  5.1 7.381 5.832 8.485 ;
     RECT  7.8 2.137 8.28 9.059 ;
     RECT  4.848 8.485 5.832 10.019 ;
     RECT  7.8 9.059 8.232 10.643 ;
     RECT  5.1 10.019 5.832 10.739 ;
     RECT  2.4 2.151 2.712 19.449 ;
     RECT  5.1 10.739 5.412 19.449 ;
     RECT  7.8 10.643 8.112 19.449 ;
     RECT  10.5 2.151 10.812 19.449 ;
     RECT  13.2 2.151 13.512 19.449 ;
     RECT  15.9 2.151 16.212 19.449 ;
     RECT  18.6 2.151 18.912 19.449 ;
     RECT  2.4 19.449 2.52 19.463 ;
     RECT  5.1 19.449 5.22 19.463 ;
     RECT  7.8 19.449 7.92 19.463 ;
     RECT  10.5 19.449 10.62 19.463 ;
     RECT  13.2 19.449 13.32 19.463 ;
     RECT  15.9 19.449 16.02 19.463 ;
     RECT  18.6 19.449 18.72 19.463 ;
  END
END hbfd_rly_48_WE
END LIBRARY
